###############################################################
#  Generated by:      Cadence Innovus 21.35-s114_1
#  OS:                Linux x86_64(Host ID pc231.ee.hacettepe.edu.tr)
#  Generated on:      Mon Dec 22 15:29:11 2025
#  Design:            mdu_macro
#  Command:           write_lef_abstract -5.8 mdu_macro.lef
###############################################################

VERSION 5.8 ;

BUSBITCHARS "[]" ;
DIVIDERCHAR "/" ;

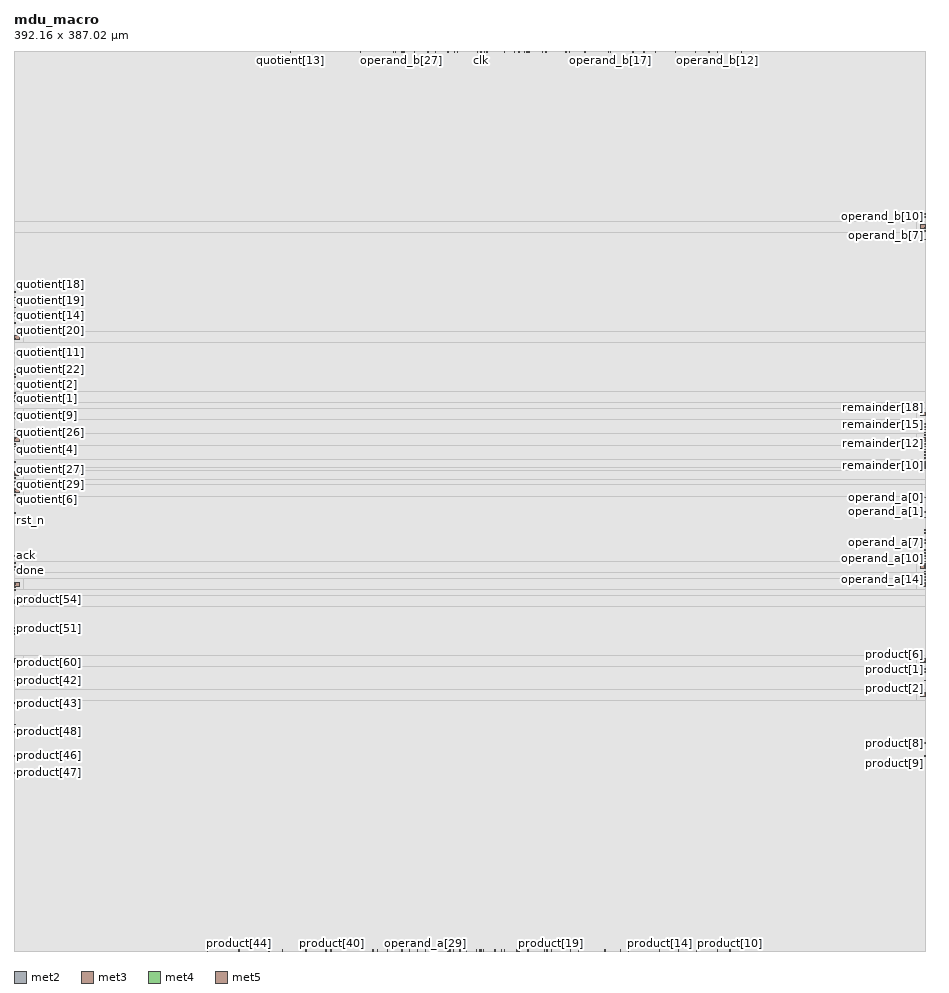
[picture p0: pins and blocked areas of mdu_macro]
MACRO mdu_macro
  CLASS BLOCK ;
  SIZE 392.160000 BY 387.020000 ;
  FOREIGN mdu_macro 0.000000 0.000000 ;
  ORIGIN 0 0 ;
  SYMMETRY X Y R90 ;
  PIN clk
    DIRECTION INPUT ;
    USE SIGNAL ;
    PORT
      LAYER met2 ;
        RECT 200.810000 386.535000 200.950000 387.020000 ;
    END
  END clk
  PIN rst_n
    DIRECTION INPUT ;
    USE SIGNAL ;
    PORT
      LAYER met3 ;
        RECT 0.000000 188.100000 0.800000 188.400000 ;
    END
  END rst_n
  PIN start
    DIRECTION INPUT ;
    USE SIGNAL ;
    PORT
      LAYER met3 ;
        RECT 0.000000 196.030000 0.800000 196.330000 ;
    END
  END start
  PIN ack
    DIRECTION INPUT ;
    USE SIGNAL ;
    PORT
      LAYER met3 ;
        RECT 0.000000 169.800000 0.800000 170.100000 ;
    END
  END ack
  PIN funct3[2]
    DIRECTION INPUT ;
    USE SIGNAL ;
    PORT
      LAYER met3 ;
        RECT 0.000000 198.470000 0.800000 198.770000 ;
    END
  END funct3[2]
  PIN funct3[1]
    DIRECTION INPUT ;
    USE SIGNAL ;
    PORT
      LAYER met2 ;
        RECT 186.410000 386.535000 186.550000 387.020000 ;
    END
  END funct3[1]
  PIN funct3[0]
    DIRECTION INPUT ;
    USE SIGNAL ;
    PORT
      LAYER met4 ;
        RECT 186.435000 386.220000 186.735000 387.020000 ;
    END
  END funct3[0]
  PIN operand_a[31]
    DIRECTION INPUT ;
    USE SIGNAL ;
    PORT
      LAYER met5 ;
        RECT 0.000000 197.210000 2.500000 198.810000 ;
    END
  END operand_a[31]
  PIN operand_a[30]
    DIRECTION INPUT ;
    USE SIGNAL ;
    PORT
      LAYER met2 ;
        RECT 170.090000 0.000000 170.230000 0.485000 ;
    END
  END operand_a[30]
  PIN operand_a[29]
    DIRECTION INPUT ;
    USE SIGNAL ;
    PORT
      LAYER met2 ;
        RECT 176.810000 0.000000 176.950000 0.485000 ;
    END
  END operand_a[29]
  PIN operand_a[28]
    DIRECTION INPUT ;
    USE SIGNAL ;
    PORT
      LAYER met2 ;
        RECT 186.410000 0.000000 186.550000 0.485000 ;
    END
  END operand_a[28]
  PIN operand_a[27]
    DIRECTION INPUT ;
    USE SIGNAL ;
    PORT
      LAYER met2 ;
        RECT 191.690000 0.000000 191.830000 0.485000 ;
    END
  END operand_a[27]
  PIN operand_a[26]
    DIRECTION INPUT ;
    USE SIGNAL ;
    PORT
      LAYER met2 ;
        RECT 198.890000 0.000000 199.030000 0.485000 ;
    END
  END operand_a[26]
  PIN operand_a[25]
    DIRECTION INPUT ;
    USE SIGNAL ;
    PORT
      LAYER met2 ;
        RECT 206.570000 0.000000 206.710000 0.485000 ;
    END
  END operand_a[25]
  PIN operand_a[24]
    DIRECTION INPUT ;
    USE SIGNAL ;
    PORT
      LAYER met2 ;
        RECT 210.890000 0.000000 211.030000 0.485000 ;
    END
  END operand_a[24]
  PIN operand_a[23]
    DIRECTION INPUT ;
    USE SIGNAL ;
    PORT
      LAYER met2 ;
        RECT 217.130000 0.000000 217.270000 0.485000 ;
    END
  END operand_a[23]
  PIN operand_a[22]
    DIRECTION INPUT ;
    USE SIGNAL ;
    PORT
      LAYER met2 ;
        RECT 220.970000 0.000000 221.110000 0.485000 ;
    END
  END operand_a[22]
  PIN operand_a[21]
    DIRECTION INPUT ;
    USE SIGNAL ;
    PORT
      LAYER met2 ;
        RECT 228.170000 0.000000 228.310000 0.485000 ;
    END
  END operand_a[21]
  PIN operand_a[20]
    DIRECTION INPUT ;
    USE SIGNAL ;
    PORT
      LAYER met3 ;
        RECT 391.360000 160.650000 392.160000 160.950000 ;
    END
  END operand_a[20]
  PIN operand_a[19]
    DIRECTION INPUT ;
    USE SIGNAL ;
    PORT
      LAYER met3 ;
        RECT 391.360000 158.210000 392.160000 158.510000 ;
    END
  END operand_a[19]
  PIN operand_a[18]
    DIRECTION INPUT ;
    USE SIGNAL ;
    PORT
      LAYER met3 ;
        RECT 391.360000 159.430000 392.160000 159.730000 ;
    END
  END operand_a[18]
  PIN operand_a[17]
    DIRECTION INPUT ;
    USE SIGNAL ;
    PORT
      LAYER met5 ;
        RECT 389.660000 156.950000 392.160000 158.550000 ;
    END
  END operand_a[17]
  PIN operand_a[16]
    DIRECTION INPUT ;
    USE SIGNAL ;
    PORT
      LAYER met3 ;
        RECT 391.360000 161.870000 392.160000 162.170000 ;
    END
  END operand_a[16]
  PIN operand_a[15]
    DIRECTION INPUT ;
    USE SIGNAL ;
    PORT
      LAYER met3 ;
        RECT 391.360000 164.920000 392.160000 165.220000 ;
    END
  END operand_a[15]
  PIN operand_a[14]
    DIRECTION INPUT ;
    USE SIGNAL ;
    PORT
      LAYER met3 ;
        RECT 391.360000 163.090000 392.160000 163.390000 ;
    END
  END operand_a[14]
  PIN operand_a[13]
    DIRECTION INPUT ;
    USE SIGNAL ;
    PORT
      LAYER met5 ;
        RECT 389.660000 164.270000 392.160000 165.870000 ;
    END
  END operand_a[13]
  PIN operand_a[12]
    DIRECTION INPUT ;
    USE SIGNAL ;
    PORT
      LAYER met3 ;
        RECT 391.360000 166.140000 392.160000 166.440000 ;
    END
  END operand_a[12]
  PIN operand_a[11]
    DIRECTION INPUT ;
    USE SIGNAL ;
    PORT
      LAYER met3 ;
        RECT 391.360000 167.360000 392.160000 167.660000 ;
    END
  END operand_a[11]
  PIN operand_a[10]
    DIRECTION INPUT ;
    USE SIGNAL ;
    PORT
      LAYER met3 ;
        RECT 391.360000 168.580000 392.160000 168.880000 ;
    END
  END operand_a[10]
  PIN operand_a[9]
    DIRECTION INPUT ;
    USE SIGNAL ;
    PORT
      LAYER met3 ;
        RECT 391.360000 169.800000 392.160000 170.100000 ;
    END
  END operand_a[9]
  PIN operand_a[8]
    DIRECTION INPUT ;
    USE SIGNAL ;
    PORT
      LAYER met3 ;
        RECT 391.360000 171.020000 392.160000 171.320000 ;
    END
  END operand_a[8]
  PIN operand_a[7]
    DIRECTION INPUT ;
    USE SIGNAL ;
    PORT
      LAYER met3 ;
        RECT 391.360000 172.240000 392.160000 172.540000 ;
    END
  END operand_a[7]
  PIN operand_a[6]
    DIRECTION INPUT ;
    USE SIGNAL ;
    PORT
      LAYER met3 ;
        RECT 391.360000 175.290000 392.160000 175.590000 ;
    END
  END operand_a[6]
  PIN operand_a[5]
    DIRECTION INPUT ;
    USE SIGNAL ;
    PORT
      LAYER met3 ;
        RECT 391.360000 176.510000 392.160000 176.810000 ;
    END
  END operand_a[5]
  PIN operand_a[4]
    DIRECTION INPUT ;
    USE SIGNAL ;
    PORT
      LAYER met3 ;
        RECT 391.360000 180.780000 392.160000 181.080000 ;
    END
  END operand_a[4]
  PIN operand_a[3]
    DIRECTION INPUT ;
    USE SIGNAL ;
    PORT
      LAYER met3 ;
        RECT 391.360000 179.560000 392.160000 179.860000 ;
    END
  END operand_a[3]
  PIN operand_a[2]
    DIRECTION INPUT ;
    USE SIGNAL ;
    PORT
      LAYER met3 ;
        RECT 391.360000 186.270000 392.160000 186.570000 ;
    END
  END operand_a[2]
  PIN operand_a[1]
    DIRECTION INPUT ;
    USE SIGNAL ;
    PORT
      LAYER met3 ;
        RECT 391.360000 188.710000 392.160000 189.010000 ;
    END
  END operand_a[1]
  PIN operand_a[0]
    DIRECTION INPUT ;
    USE SIGNAL ;
    PORT
      LAYER met3 ;
        RECT 391.360000 194.810000 392.160000 195.110000 ;
    END
  END operand_a[0]
  PIN operand_b[31]
    DIRECTION INPUT ;
    USE SIGNAL ;
    PORT
      LAYER met2 ;
        RECT 178.250000 386.535000 178.390000 387.020000 ;
    END
  END operand_b[31]
  PIN operand_b[30]
    DIRECTION INPUT ;
    USE SIGNAL ;
    PORT
      LAYER met2 ;
        RECT 172.010000 386.535000 172.150000 387.020000 ;
    END
  END operand_b[30]
  PIN operand_b[29]
    DIRECTION INPUT ;
    USE SIGNAL ;
    PORT
      LAYER met2 ;
        RECT 167.690000 386.535000 167.830000 387.020000 ;
    END
  END operand_b[29]
  PIN operand_b[28]
    DIRECTION INPUT ;
    USE SIGNAL ;
    PORT
      LAYER met2 ;
        RECT 163.850000 386.535000 163.990000 387.020000 ;
    END
  END operand_b[28]
  PIN operand_b[27]
    DIRECTION INPUT ;
    USE SIGNAL ;
    PORT
      LAYER met2 ;
        RECT 166.730000 386.535000 166.870000 387.020000 ;
    END
  END operand_b[27]
  PIN operand_b[26]
    DIRECTION INPUT ;
    USE SIGNAL ;
    PORT
      LAYER met2 ;
        RECT 181.130000 386.535000 181.270000 387.020000 ;
    END
  END operand_b[26]
  PIN operand_b[25]
    DIRECTION INPUT ;
    USE SIGNAL ;
    PORT
      LAYER met2 ;
        RECT 189.290000 386.535000 189.430000 387.020000 ;
    END
  END operand_b[25]
  PIN operand_b[24]
    DIRECTION INPUT ;
    USE SIGNAL ;
    PORT
      LAYER met2 ;
        RECT 202.250000 386.535000 202.390000 387.020000 ;
    END
  END operand_b[24]
  PIN operand_b[23]
    DIRECTION INPUT ;
    USE SIGNAL ;
    PORT
      LAYER met2 ;
        RECT 203.690000 386.535000 203.830000 387.020000 ;
    END
  END operand_b[23]
  PIN operand_b[22]
    DIRECTION INPUT ;
    USE SIGNAL ;
    PORT
      LAYER met2 ;
        RECT 210.890000 386.535000 211.030000 387.020000 ;
    END
  END operand_b[22]
  PIN operand_b[21]
    DIRECTION INPUT ;
    USE SIGNAL ;
    PORT
      LAYER met2 ;
        RECT 220.490000 386.535000 220.630000 387.020000 ;
    END
  END operand_b[21]
  PIN operand_b[20]
    DIRECTION INPUT ;
    USE SIGNAL ;
    PORT
      LAYER met2 ;
        RECT 227.210000 386.535000 227.350000 387.020000 ;
    END
  END operand_b[20]
  PIN operand_b[19]
    DIRECTION INPUT ;
    USE SIGNAL ;
    PORT
      LAYER met2 ;
        RECT 238.730000 386.535000 238.870000 387.020000 ;
    END
  END operand_b[19]
  PIN operand_b[18]
    DIRECTION INPUT ;
    USE SIGNAL ;
    PORT
      LAYER met2 ;
        RECT 245.450000 386.535000 245.590000 387.020000 ;
    END
  END operand_b[18]
  PIN operand_b[17]
    DIRECTION INPUT ;
    USE SIGNAL ;
    PORT
      LAYER met2 ;
        RECT 256.490000 386.535000 256.630000 387.020000 ;
    END
  END operand_b[17]
  PIN operand_b[16]
    DIRECTION INPUT ;
    USE SIGNAL ;
    PORT
      LAYER met2 ;
        RECT 266.090000 386.535000 266.230000 387.020000 ;
    END
  END operand_b[16]
  PIN operand_b[15]
    DIRECTION INPUT ;
    USE SIGNAL ;
    PORT
      LAYER met2 ;
        RECT 275.690000 386.535000 275.830000 387.020000 ;
    END
  END operand_b[15]
  PIN operand_b[14]
    DIRECTION INPUT ;
    USE SIGNAL ;
    PORT
      LAYER met2 ;
        RECT 284.330000 386.535000 284.470000 387.020000 ;
    END
  END operand_b[14]
  PIN operand_b[13]
    DIRECTION INPUT ;
    USE SIGNAL ;
    PORT
      LAYER met2 ;
        RECT 292.970000 386.535000 293.110000 387.020000 ;
    END
  END operand_b[13]
  PIN operand_b[12]
    DIRECTION INPUT ;
    USE SIGNAL ;
    PORT
      LAYER met2 ;
        RECT 302.570000 386.535000 302.710000 387.020000 ;
    END
  END operand_b[12]
  PIN operand_b[11]
    DIRECTION INPUT ;
    USE SIGNAL ;
    PORT
      LAYER met3 ;
        RECT 391.360000 316.810000 392.160000 317.110000 ;
    END
  END operand_b[11]
  PIN operand_b[10]
    DIRECTION INPUT ;
    USE SIGNAL ;
    PORT
      LAYER met3 ;
        RECT 391.360000 315.590000 392.160000 315.890000 ;
    END
  END operand_b[10]
  PIN operand_b[9]
    DIRECTION INPUT ;
    USE SIGNAL ;
    PORT
      LAYER met3 ;
        RECT 391.360000 309.490000 392.160000 309.790000 ;
    END
  END operand_b[9]
  PIN operand_b[8]
    DIRECTION INPUT ;
    USE SIGNAL ;
    PORT
      LAYER met3 ;
        RECT 391.360000 305.830000 392.160000 306.130000 ;
    END
  END operand_b[8]
  PIN operand_b[7]
    DIRECTION INPUT ;
    USE SIGNAL ;
    PORT
      LAYER met3 ;
        RECT 391.360000 310.710000 392.160000 311.010000 ;
    END
  END operand_b[7]
  PIN operand_b[6]
    DIRECTION INPUT ;
    USE SIGNAL ;
    PORT
      LAYER met5 ;
        RECT 389.660000 310.670000 392.160000 312.270000 ;
    END
  END operand_b[6]
  PIN operand_b[5]
    DIRECTION INPUT ;
    USE SIGNAL ;
    PORT
      LAYER met2 ;
        RECT 312.650000 386.535000 312.790000 387.020000 ;
    END
  END operand_b[5]
  PIN operand_b[4]
    DIRECTION INPUT ;
    USE SIGNAL ;
    PORT
      LAYER met2 ;
        RECT 298.730000 386.535000 298.870000 387.020000 ;
    END
  END operand_b[4]
  PIN operand_b[3]
    DIRECTION INPUT ;
    USE SIGNAL ;
    PORT
      LAYER met2 ;
        RECT 270.890000 386.535000 271.030000 387.020000 ;
    END
  END operand_b[3]
  PIN operand_b[2]
    DIRECTION INPUT ;
    USE SIGNAL ;
    PORT
      LAYER met2 ;
        RECT 255.530000 386.535000 255.670000 387.020000 ;
    END
  END operand_b[2]
  PIN operand_b[1]
    DIRECTION INPUT ;
    USE SIGNAL ;
    PORT
      LAYER met2 ;
        RECT 237.290000 386.535000 237.430000 387.020000 ;
    END
  END operand_b[1]
  PIN operand_b[0]
    DIRECTION INPUT ;
    USE SIGNAL ;
    PORT
      LAYER met2 ;
        RECT 219.530000 386.535000 219.670000 387.020000 ;
    END
  END operand_b[0]
  PIN busy
    DIRECTION OUTPUT ;
    USE SIGNAL ;
    PORT
      LAYER met5 ;
        RECT 0.000000 204.530000 2.500000 206.130000 ;
    END
  END busy
  PIN done
    DIRECTION OUTPUT ;
    USE SIGNAL ;
    PORT
      LAYER met3 ;
        RECT 0.000000 166.750000 0.800000 167.050000 ;
    END
  END done
  PIN product[63]
    DIRECTION OUTPUT ;
    USE SIGNAL ;
    PORT
      LAYER met3 ;
        RECT 0.000000 156.380000 0.800000 156.680000 ;
    END
  END product[63]
  PIN product[62]
    DIRECTION OUTPUT ;
    USE SIGNAL ;
    PORT
      LAYER met3 ;
        RECT 0.000000 137.470000 0.800000 137.770000 ;
    END
  END product[62]
  PIN product[61]
    DIRECTION OUTPUT ;
    USE SIGNAL ;
    PORT
      LAYER met2 ;
        RECT 125.450000 0.000000 125.590000 0.485000 ;
    END
  END product[61]
  PIN product[60]
    DIRECTION OUTPUT ;
    USE SIGNAL ;
    PORT
      LAYER met3 ;
        RECT 0.000000 124.050000 0.800000 124.350000 ;
    END
  END product[60]
  PIN product[59]
    DIRECTION OUTPUT ;
    USE SIGNAL ;
    PORT
      LAYER met3 ;
        RECT 0.000000 136.250000 0.800000 136.550000 ;
    END
  END product[59]
  PIN product[58]
    DIRECTION OUTPUT ;
    USE SIGNAL ;
    PORT
      LAYER met3 ;
        RECT 0.000000 155.160000 0.800000 155.460000 ;
    END
  END product[58]
  PIN product[57]
    DIRECTION OUTPUT ;
    USE SIGNAL ;
    PORT
      LAYER met3 ;
        RECT 0.000000 163.700000 0.800000 164.000000 ;
    END
  END product[57]
  PIN product[56]
    DIRECTION OUTPUT ;
    USE SIGNAL ;
    PORT
      LAYER met3 ;
        RECT 0.000000 164.920000 0.800000 165.220000 ;
    END
  END product[56]
  PIN product[55]
    DIRECTION OUTPUT ;
    USE SIGNAL ;
    PORT
      LAYER met3 ;
        RECT 0.000000 157.600000 0.800000 157.900000 ;
    END
  END product[55]
  PIN product[54]
    DIRECTION OUTPUT ;
    USE SIGNAL ;
    PORT
      LAYER met3 ;
        RECT 0.000000 150.890000 0.800000 151.190000 ;
    END
  END product[54]
  PIN product[53]
    DIRECTION OUTPUT ;
    USE SIGNAL ;
    PORT
      LAYER met5 ;
        RECT 0.000000 156.950000 2.500000 158.550000 ;
    END
  END product[53]
  PIN product[52]
    DIRECTION OUTPUT ;
    USE SIGNAL ;
    PORT
      LAYER met5 ;
        RECT 0.000000 149.630000 2.500000 151.230000 ;
    END
  END product[52]
  PIN product[51]
    DIRECTION OUTPUT ;
    USE SIGNAL ;
    PORT
      LAYER met3 ;
        RECT 0.000000 138.690000 0.800000 138.990000 ;
    END
  END product[51]
  PIN product[50]
    DIRECTION OUTPUT ;
    USE SIGNAL ;
    PORT
      LAYER met5 ;
        RECT 0.000000 124.010000 2.500000 125.610000 ;
    END
  END product[50]
  PIN product[49]
    DIRECTION OUTPUT ;
    USE SIGNAL ;
    PORT
      LAYER met3 ;
        RECT 0.000000 97.210000 0.800000 97.510000 ;
    END
  END product[49]
  PIN product[48]
    DIRECTION OUTPUT ;
    USE SIGNAL ;
    PORT
      LAYER met3 ;
        RECT 0.000000 94.160000 0.800000 94.460000 ;
    END
  END product[48]
  PIN product[47]
    DIRECTION OUTPUT ;
    USE SIGNAL ;
    PORT
      LAYER met3 ;
        RECT 0.000000 76.470000 0.800000 76.770000 ;
    END
  END product[47]
  PIN product[46]
    DIRECTION OUTPUT ;
    USE SIGNAL ;
    PORT
      LAYER met3 ;
        RECT 0.000000 83.790000 0.800000 84.090000 ;
    END
  END product[46]
  PIN product[45]
    DIRECTION OUTPUT ;
    USE SIGNAL ;
    PORT
      LAYER met2 ;
        RECT 83.210000 0.000000 83.350000 0.485000 ;
    END
  END product[45]
  PIN product[44]
    DIRECTION OUTPUT ;
    USE SIGNAL ;
    PORT
      LAYER met2 ;
        RECT 96.650000 0.000000 96.790000 0.485000 ;
    END
  END product[44]
  PIN product[43]
    DIRECTION OUTPUT ;
    USE SIGNAL ;
    PORT
      LAYER met3 ;
        RECT 0.000000 106.360000 0.800000 106.660000 ;
    END
  END product[43]
  PIN product[42]
    DIRECTION OUTPUT ;
    USE SIGNAL ;
    PORT
      LAYER met3 ;
        RECT 0.000000 116.120000 0.800000 116.420000 ;
    END
  END product[42]
  PIN product[41]
    DIRECTION OUTPUT ;
    USE SIGNAL ;
    PORT
      LAYER met2 ;
        RECT 134.090000 0.000000 134.230000 0.485000 ;
    END
  END product[41]
  PIN product[40]
    DIRECTION OUTPUT ;
    USE SIGNAL ;
    PORT
      LAYER met2 ;
        RECT 136.490000 0.000000 136.630000 0.485000 ;
    END
  END product[40]
  PIN product[39]
    DIRECTION OUTPUT ;
    USE SIGNAL ;
    PORT
      LAYER met2 ;
        RECT 109.610000 0.000000 109.750000 0.485000 ;
    END
  END product[39]
  PIN product[38]
    DIRECTION OUTPUT ;
    USE SIGNAL ;
    PORT
      LAYER met2 ;
        RECT 115.370000 0.000000 115.510000 0.485000 ;
    END
  END product[38]
  PIN product[37]
    DIRECTION OUTPUT ;
    USE SIGNAL ;
    PORT
      LAYER met4 ;
        RECT 136.005000 0.000000 136.305000 0.800000 ;
    END
  END product[37]
  PIN product[36]
    DIRECTION OUTPUT ;
    USE SIGNAL ;
    PORT
      LAYER met2 ;
        RECT 154.250000 0.000000 154.390000 0.485000 ;
    END
  END product[36]
  PIN product[35]
    DIRECTION OUTPUT ;
    USE SIGNAL ;
    PORT
      LAYER met2 ;
        RECT 166.730000 0.000000 166.870000 0.485000 ;
    END
  END product[35]
  PIN product[34]
    DIRECTION OUTPUT ;
    USE SIGNAL ;
    PORT
      LAYER met2 ;
        RECT 200.330000 0.000000 200.470000 0.485000 ;
    END
  END product[34]
  PIN product[33]
    DIRECTION OUTPUT ;
    USE SIGNAL ;
    PORT
      LAYER met2 ;
        RECT 194.570000 0.000000 194.710000 0.485000 ;
    END
  END product[33]
  PIN product[32]
    DIRECTION OUTPUT ;
    USE SIGNAL ;
    PORT
      LAYER met2 ;
        RECT 188.810000 0.000000 188.950000 0.485000 ;
    END
  END product[32]
  PIN product[31]
    DIRECTION OUTPUT ;
    USE SIGNAL ;
    PORT
      LAYER met2 ;
        RECT 187.370000 0.000000 187.510000 0.485000 ;
    END
  END product[31]
  PIN product[30]
    DIRECTION OUTPUT ;
    USE SIGNAL ;
    PORT
      LAYER met2 ;
        RECT 173.450000 0.000000 173.590000 0.485000 ;
    END
  END product[30]
  PIN product[29]
    DIRECTION OUTPUT ;
    USE SIGNAL ;
    PORT
      LAYER met2 ;
        RECT 160.490000 0.000000 160.630000 0.485000 ;
    END
  END product[29]
  PIN product[28]
    DIRECTION OUTPUT ;
    USE SIGNAL ;
    PORT
      LAYER met2 ;
        RECT 156.170000 0.000000 156.310000 0.485000 ;
    END
  END product[28]
  PIN product[27]
    DIRECTION OUTPUT ;
    USE SIGNAL ;
    PORT
      LAYER met4 ;
        RECT 186.435000 0.000000 186.735000 0.800000 ;
    END
  END product[27]
  PIN product[26]
    DIRECTION OUTPUT ;
    USE SIGNAL ;
    PORT
      LAYER met4 ;
        RECT 200.580000 0.000000 200.880000 0.800000 ;
    END
  END product[26]
  PIN product[25]
    DIRECTION OUTPUT ;
    USE SIGNAL ;
    PORT
      LAYER met2 ;
        RECT 201.770000 0.000000 201.910000 0.485000 ;
    END
  END product[25]
  PIN product[24]
    DIRECTION OUTPUT ;
    USE SIGNAL ;
    PORT
      LAYER met4 ;
        RECT 206.730000 0.000000 207.030000 0.800000 ;
    END
  END product[24]
  PIN product[23]
    DIRECTION OUTPUT ;
    USE SIGNAL ;
    PORT
      LAYER met2 ;
        RECT 209.450000 0.000000 209.590000 0.485000 ;
    END
  END product[23]
  PIN product[22]
    DIRECTION OUTPUT ;
    USE SIGNAL ;
    PORT
      LAYER met4 ;
        RECT 220.875000 0.000000 221.175000 0.800000 ;
    END
  END product[22]
  PIN product[21]
    DIRECTION OUTPUT ;
    USE SIGNAL ;
    PORT
      LAYER met2 ;
        RECT 229.130000 0.000000 229.270000 0.485000 ;
    END
  END product[21]
  PIN product[20]
    DIRECTION OUTPUT ;
    USE SIGNAL ;
    PORT
      LAYER met2 ;
        RECT 239.210000 0.000000 239.350000 0.485000 ;
    END
  END product[20]
  PIN product[19]
    DIRECTION OUTPUT ;
    USE SIGNAL ;
    PORT
      LAYER met2 ;
        RECT 231.050000 0.000000 231.190000 0.485000 ;
    END
  END product[19]
  PIN product[18]
    DIRECTION OUTPUT ;
    USE SIGNAL ;
    PORT
      LAYER met2 ;
        RECT 242.570000 0.000000 242.710000 0.485000 ;
    END
  END product[18]
  PIN product[17]
    DIRECTION OUTPUT ;
    USE SIGNAL ;
    PORT
      LAYER met2 ;
        RECT 254.090000 0.000000 254.230000 0.485000 ;
    END
  END product[17]
  PIN product[16]
    DIRECTION OUTPUT ;
    USE SIGNAL ;
    PORT
      LAYER met2 ;
        RECT 260.810000 0.000000 260.950000 0.485000 ;
    END
  END product[16]
  PIN product[15]
    DIRECTION OUTPUT ;
    USE SIGNAL ;
    PORT
      LAYER met2 ;
        RECT 264.170000 0.000000 264.310000 0.485000 ;
    END
  END product[15]
  PIN product[14]
    DIRECTION OUTPUT ;
    USE SIGNAL ;
    PORT
      LAYER met2 ;
        RECT 277.610000 0.000000 277.750000 0.485000 ;
    END
  END product[14]
  PIN product[13]
    DIRECTION OUTPUT ;
    USE SIGNAL ;
    PORT
      LAYER met2 ;
        RECT 285.770000 0.000000 285.910000 0.485000 ;
    END
  END product[13]
  PIN product[12]
    DIRECTION OUTPUT ;
    USE SIGNAL ;
    PORT
      LAYER met2 ;
        RECT 293.450000 0.000000 293.590000 0.485000 ;
    END
  END product[12]
  PIN product[11]
    DIRECTION OUTPUT ;
    USE SIGNAL ;
    PORT
      LAYER met2 ;
        RECT 302.570000 0.000000 302.710000 0.485000 ;
    END
  END product[11]
  PIN product[10]
    DIRECTION OUTPUT ;
    USE SIGNAL ;
    PORT
      LAYER met2 ;
        RECT 307.850000 0.000000 307.990000 0.485000 ;
    END
  END product[10]
  PIN product[9]
    DIRECTION OUTPUT ;
    USE SIGNAL ;
    PORT
      LAYER met3 ;
        RECT 391.360000 83.790000 392.160000 84.090000 ;
    END
  END product[9]
  PIN product[8]
    DIRECTION OUTPUT ;
    USE SIGNAL ;
    PORT
      LAYER met3 ;
        RECT 391.360000 89.280000 392.160000 89.580000 ;
    END
  END product[8]
  PIN product[7]
    DIRECTION OUTPUT ;
    USE SIGNAL ;
    PORT
      LAYER met3 ;
        RECT 391.360000 110.630000 392.160000 110.930000 ;
    END
  END product[7]
  PIN product[6]
    DIRECTION OUTPUT ;
    USE SIGNAL ;
    PORT
      LAYER met3 ;
        RECT 391.360000 124.050000 392.160000 124.350000 ;
    END
  END product[6]
  PIN product[5]
    DIRECTION OUTPUT ;
    USE SIGNAL ;
    PORT
      LAYER met5 ;
        RECT 389.660000 124.010000 392.160000 125.610000 ;
    END
  END product[5]
  PIN product[4]
    DIRECTION OUTPUT ;
    USE SIGNAL ;
    PORT
      LAYER met5 ;
        RECT 389.660000 109.370000 392.160000 110.970000 ;
    END
  END product[4]
  PIN product[3]
    DIRECTION OUTPUT ;
    USE SIGNAL ;
    PORT
      LAYER met3 ;
        RECT 391.360000 119.780000 392.160000 120.080000 ;
    END
  END product[3]
  PIN product[2]
    DIRECTION OUTPUT ;
    USE SIGNAL ;
    PORT
      LAYER met3 ;
        RECT 391.360000 116.120000 392.160000 116.420000 ;
    END
  END product[2]
  PIN product[1]
    DIRECTION OUTPUT ;
    USE SIGNAL ;
    PORT
      LAYER met3 ;
        RECT 391.360000 121.000000 392.160000 121.300000 ;
    END
  END product[1]
  PIN product[0]
    DIRECTION OUTPUT ;
    USE SIGNAL ;
    PORT
      LAYER met2 ;
        RECT 216.170000 0.000000 216.310000 0.485000 ;
    END
  END product[0]
  PIN quotient[31]
    DIRECTION OUTPUT ;
    USE SIGNAL ;
    PORT
      LAYER met3 ;
        RECT 0.000000 220.430000 0.800000 220.730000 ;
    END
  END quotient[31]
  PIN quotient[30]
    DIRECTION OUTPUT ;
    USE SIGNAL ;
    PORT
      LAYER met5 ;
        RECT 0.000000 219.170000 2.500000 220.770000 ;
    END
  END quotient[30]
  PIN quotient[29]
    DIRECTION OUTPUT ;
    USE SIGNAL ;
    PORT
      LAYER met3 ;
        RECT 0.000000 200.300000 0.800000 200.600000 ;
    END
  END quotient[29]
  PIN quotient[28]
    DIRECTION OUTPUT ;
    USE SIGNAL ;
    PORT
      LAYER met3 ;
        RECT 0.000000 203.350000 0.800000 203.650000 ;
    END
  END quotient[28]
  PIN quotient[27]
    DIRECTION OUTPUT ;
    USE SIGNAL ;
    PORT
      LAYER met3 ;
        RECT 0.000000 210.060000 0.800000 210.360000 ;
    END
  END quotient[27]
  PIN quotient[26]
    DIRECTION OUTPUT ;
    USE SIGNAL ;
    PORT
      LAYER met3 ;
        RECT 0.000000 222.870000 0.800000 223.170000 ;
    END
  END quotient[26]
  PIN quotient[25]
    DIRECTION OUTPUT ;
    USE SIGNAL ;
    PORT
      LAYER met3 ;
        RECT 0.000000 236.290000 0.800000 236.590000 ;
    END
  END quotient[25]
  PIN quotient[24]
    DIRECTION OUTPUT ;
    USE SIGNAL ;
    PORT
      LAYER met3 ;
        RECT 0.000000 246.660000 0.800000 246.960000 ;
    END
  END quotient[24]
  PIN quotient[23]
    DIRECTION OUTPUT ;
    USE SIGNAL ;
    PORT
      LAYER met3 ;
        RECT 0.000000 239.950000 0.800000 240.250000 ;
    END
  END quotient[23]
  PIN quotient[22]
    DIRECTION OUTPUT ;
    USE SIGNAL ;
    PORT
      LAYER met3 ;
        RECT 0.000000 249.710000 0.800000 250.010000 ;
    END
  END quotient[22]
  PIN quotient[21]
    DIRECTION OUTPUT ;
    USE SIGNAL ;
    PORT
      LAYER met3 ;
        RECT 0.000000 263.130000 0.800000 263.430000 ;
    END
  END quotient[21]
  PIN quotient[20]
    DIRECTION OUTPUT ;
    USE SIGNAL ;
    PORT
      LAYER met3 ;
        RECT 0.000000 269.840000 0.800000 270.140000 ;
    END
  END quotient[20]
  PIN quotient[19]
    DIRECTION OUTPUT ;
    USE SIGNAL ;
    PORT
      LAYER met3 ;
        RECT 0.000000 279.600000 0.800000 279.900000 ;
    END
  END quotient[19]
  PIN quotient[18]
    DIRECTION OUTPUT ;
    USE SIGNAL ;
    PORT
      LAYER met3 ;
        RECT 0.000000 283.260000 0.800000 283.560000 ;
    END
  END quotient[18]
  PIN quotient[17]
    DIRECTION OUTPUT ;
    USE SIGNAL ;
    PORT
      LAYER met3 ;
        RECT 0.000000 280.820000 0.800000 281.120000 ;
    END
  END quotient[17]
  PIN quotient[16]
    DIRECTION OUTPUT ;
    USE SIGNAL ;
    PORT
      LAYER met3 ;
        RECT 0.000000 272.890000 0.800000 273.190000 ;
    END
  END quotient[16]
  PIN quotient[15]
    DIRECTION OUTPUT ;
    USE SIGNAL ;
    PORT
      LAYER met3 ;
        RECT 0.000000 274.110000 0.800000 274.410000 ;
    END
  END quotient[15]
  PIN quotient[14]
    DIRECTION OUTPUT ;
    USE SIGNAL ;
    PORT
      LAYER met3 ;
        RECT 0.000000 276.550000 0.800000 276.850000 ;
    END
  END quotient[14]
  PIN quotient[13]
    DIRECTION OUTPUT ;
    USE SIGNAL ;
    PORT
      LAYER met2 ;
        RECT 118.730000 386.535000 118.870000 387.020000 ;
    END
  END quotient[13]
  PIN quotient[12]
    DIRECTION OUTPUT ;
    USE SIGNAL ;
    PORT
      LAYER met5 ;
        RECT 0.000000 263.090000 2.500000 264.690000 ;
    END
  END quotient[12]
  PIN quotient[11]
    DIRECTION OUTPUT ;
    USE SIGNAL ;
    PORT
      LAYER met3 ;
        RECT 0.000000 257.030000 0.800000 257.330000 ;
    END
  END quotient[11]
  PIN quotient[10]
    DIRECTION OUTPUT ;
    USE SIGNAL ;
    PORT
      LAYER met3 ;
        RECT 0.000000 247.880000 0.800000 248.180000 ;
    END
  END quotient[10]
  PIN quotient[9]
    DIRECTION OUTPUT ;
    USE SIGNAL ;
    PORT
      LAYER met3 ;
        RECT 0.000000 230.190000 0.800000 230.490000 ;
    END
  END quotient[9]
  PIN quotient[8]
    DIRECTION OUTPUT ;
    USE SIGNAL ;
    PORT
      LAYER met3 ;
        RECT 0.000000 216.770000 0.800000 217.070000 ;
    END
  END quotient[8]
  PIN quotient[7]
    DIRECTION OUTPUT ;
    USE SIGNAL ;
    PORT
      LAYER met3 ;
        RECT 0.000000 201.520000 0.800000 201.820000 ;
    END
  END quotient[7]
  PIN quotient[6]
    DIRECTION OUTPUT ;
    USE SIGNAL ;
    PORT
      LAYER met3 ;
        RECT 0.000000 197.250000 0.800000 197.550000 ;
    END
  END quotient[6]
  PIN quotient[5]
    DIRECTION OUTPUT ;
    USE SIGNAL ;
    PORT
      LAYER met3 ;
        RECT 0.000000 204.570000 0.800000 204.870000 ;
    END
  END quotient[5]
  PIN quotient[4]
    DIRECTION OUTPUT ;
    USE SIGNAL ;
    PORT
      LAYER met3 ;
        RECT 0.000000 215.550000 0.800000 215.850000 ;
    END
  END quotient[4]
  PIN quotient[3]
    DIRECTION OUTPUT ;
    USE SIGNAL ;
    PORT
      LAYER met5 ;
        RECT 0.000000 230.150000 2.500000 231.750000 ;
    END
  END quotient[3]
  PIN quotient[2]
    DIRECTION OUTPUT ;
    USE SIGNAL ;
    PORT
      LAYER met3 ;
        RECT 0.000000 243.610000 0.800000 243.910000 ;
    END
  END quotient[2]
  PIN quotient[1]
    DIRECTION OUTPUT ;
    USE SIGNAL ;
    PORT
      LAYER met3 ;
        RECT 0.000000 237.510000 0.800000 237.810000 ;
    END
  END quotient[1]
  PIN quotient[0]
    DIRECTION OUTPUT ;
    USE SIGNAL ;
    PORT
      LAYER met5 ;
        RECT 0.000000 237.470000 2.500000 239.070000 ;
    END
  END quotient[0]
  PIN remainder[31]
    DIRECTION OUTPUT ;
    USE SIGNAL ;
    PORT
      LAYER met2 ;
        RECT 148.970000 386.535000 149.110000 387.020000 ;
    END
  END remainder[31]
  PIN remainder[30]
    DIRECTION OUTPUT ;
    USE SIGNAL ;
    PORT
      LAYER met3 ;
        RECT 0.000000 217.990000 0.800000 218.290000 ;
    END
  END remainder[30]
  PIN remainder[29]
    DIRECTION OUTPUT ;
    USE SIGNAL ;
    PORT
      LAYER met3 ;
        RECT 0.000000 224.090000 0.800000 224.390000 ;
    END
  END remainder[29]
  PIN remainder[28]
    DIRECTION OUTPUT ;
    USE SIGNAL ;
    PORT
      LAYER met3 ;
        RECT 0.000000 228.970000 0.800000 229.270000 ;
    END
  END remainder[28]
  PIN remainder[27]
    DIRECTION OUTPUT ;
    USE SIGNAL ;
    PORT
      LAYER met4 ;
        RECT 163.065000 386.220000 163.365000 387.020000 ;
    END
  END remainder[27]
  PIN remainder[26]
    DIRECTION OUTPUT ;
    USE SIGNAL ;
    PORT
      LAYER met4 ;
        RECT 177.825000 386.220000 178.125000 387.020000 ;
    END
  END remainder[26]
  PIN remainder[25]
    DIRECTION OUTPUT ;
    USE SIGNAL ;
    PORT
      LAYER met2 ;
        RECT 190.730000 386.535000 190.870000 387.020000 ;
    END
  END remainder[25]
  PIN remainder[24]
    DIRECTION OUTPUT ;
    USE SIGNAL ;
    PORT
      LAYER met2 ;
        RECT 199.370000 386.535000 199.510000 387.020000 ;
    END
  END remainder[24]
  PIN remainder[23]
    DIRECTION OUTPUT ;
    USE SIGNAL ;
    PORT
      LAYER met2 ;
        RECT 215.210000 386.535000 215.350000 387.020000 ;
    END
  END remainder[23]
  PIN remainder[22]
    DIRECTION OUTPUT ;
    USE SIGNAL ;
    PORT
      LAYER met4 ;
        RECT 203.040000 386.220000 203.340000 387.020000 ;
    END
  END remainder[22]
  PIN remainder[21]
    DIRECTION OUTPUT ;
    USE SIGNAL ;
    PORT
      LAYER met2 ;
        RECT 217.130000 386.535000 217.270000 387.020000 ;
    END
  END remainder[21]
  PIN remainder[20]
    DIRECTION OUTPUT ;
    USE SIGNAL ;
    PORT
      LAYER met2 ;
        RECT 221.450000 386.535000 221.590000 387.020000 ;
    END
  END remainder[20]
  PIN remainder[19]
    DIRECTION OUTPUT ;
    USE SIGNAL ;
    PORT
      LAYER met2 ;
        RECT 228.650000 386.535000 228.790000 387.020000 ;
    END
  END remainder[19]
  PIN remainder[18]
    DIRECTION OUTPUT ;
    USE SIGNAL ;
    PORT
      LAYER met3 ;
        RECT 391.360000 230.190000 392.160000 230.490000 ;
    END
  END remainder[18]
  PIN remainder[17]
    DIRECTION OUTPUT ;
    USE SIGNAL ;
    PORT
      LAYER met3 ;
        RECT 391.360000 219.820000 392.160000 220.120000 ;
    END
  END remainder[17]
  PIN remainder[16]
    DIRECTION OUTPUT ;
    USE SIGNAL ;
    PORT
      LAYER met5 ;
        RECT 389.660000 219.170000 392.160000 220.770000 ;
    END
  END remainder[16]
  PIN remainder[15]
    DIRECTION OUTPUT ;
    USE SIGNAL ;
    PORT
      LAYER met3 ;
        RECT 391.360000 222.870000 392.160000 223.170000 ;
    END
  END remainder[15]
  PIN remainder[14]
    DIRECTION OUTPUT ;
    USE SIGNAL ;
    PORT
      LAYER met3 ;
        RECT 391.360000 216.770000 392.160000 217.070000 ;
    END
  END remainder[14]
  PIN remainder[13]
    DIRECTION OUTPUT ;
    USE SIGNAL ;
    PORT
      LAYER met3 ;
        RECT 391.360000 215.550000 392.160000 215.850000 ;
    END
  END remainder[13]
  PIN remainder[12]
    DIRECTION OUTPUT ;
    USE SIGNAL ;
    PORT
      LAYER met3 ;
        RECT 391.360000 217.990000 392.160000 218.290000 ;
    END
  END remainder[12]
  PIN remainder[11]
    DIRECTION OUTPUT ;
    USE SIGNAL ;
    PORT
      LAYER met3 ;
        RECT 391.360000 210.060000 392.160000 210.360000 ;
    END
  END remainder[11]
  PIN remainder[10]
    DIRECTION OUTPUT ;
    USE SIGNAL ;
    PORT
      LAYER met3 ;
        RECT 391.360000 208.840000 392.160000 209.140000 ;
    END
  END remainder[10]
  PIN remainder[9]
    DIRECTION OUTPUT ;
    USE SIGNAL ;
    PORT
      LAYER met5 ;
        RECT 389.660000 230.150000 392.160000 231.750000 ;
    END
  END remainder[9]
  PIN remainder[8]
    DIRECTION OUTPUT ;
    USE SIGNAL ;
    PORT
      LAYER met3 ;
        RECT 391.360000 224.090000 392.160000 224.390000 ;
    END
  END remainder[8]
  PIN remainder[7]
    DIRECTION OUTPUT ;
    USE SIGNAL ;
    PORT
      LAYER met3 ;
        RECT 391.360000 214.330000 392.160000 214.630000 ;
    END
  END remainder[7]
  PIN remainder[6]
    DIRECTION OUTPUT ;
    USE SIGNAL ;
    PORT
      LAYER met3 ;
        RECT 391.360000 213.110000 392.160000 213.410000 ;
    END
  END remainder[6]
  PIN remainder[5]
    DIRECTION OUTPUT ;
    USE SIGNAL ;
    PORT
      LAYER met3 ;
        RECT 391.360000 221.650000 392.160000 221.950000 ;
    END
  END remainder[5]
  PIN remainder[4]
    DIRECTION OUTPUT ;
    USE SIGNAL ;
    PORT
      LAYER met5 ;
        RECT 389.660000 208.190000 392.160000 209.790000 ;
    END
  END remainder[4]
  PIN remainder[3]
    DIRECTION OUTPUT ;
    USE SIGNAL ;
    PORT
      LAYER met3 ;
        RECT 391.360000 211.890000 392.160000 212.190000 ;
    END
  END remainder[3]
  PIN remainder[2]
    DIRECTION OUTPUT ;
    USE SIGNAL ;
    PORT
      LAYER met3 ;
        RECT 391.360000 207.620000 392.160000 207.920000 ;
    END
  END remainder[2]
  PIN remainder[1]
    DIRECTION OUTPUT ;
    USE SIGNAL ;
    PORT
      LAYER met3 ;
        RECT 391.360000 225.310000 392.160000 225.610000 ;
    END
  END remainder[1]
  PIN remainder[0]
    DIRECTION OUTPUT ;
    USE SIGNAL ;
    PORT
      LAYER met3 ;
        RECT 391.360000 226.530000 392.160000 226.830000 ;
    END
  END remainder[0]
  OBS
    LAYER met1 ;
      RECT 0.000000 0.000000 392.160000 387.020000 ;
    LAYER met2 ;
      RECT 312.930000 386.395000 392.160000 387.020000 ;
      RECT 302.850000 386.395000 312.510000 387.020000 ;
      RECT 299.010000 386.395000 302.430000 387.020000 ;
      RECT 293.250000 386.395000 298.590000 387.020000 ;
      RECT 284.610000 386.395000 292.830000 387.020000 ;
      RECT 275.970000 386.395000 284.190000 387.020000 ;
      RECT 271.170000 386.395000 275.550000 387.020000 ;
      RECT 266.370000 386.395000 270.750000 387.020000 ;
      RECT 256.770000 386.395000 265.950000 387.020000 ;
      RECT 255.810000 386.395000 256.350000 387.020000 ;
      RECT 245.730000 386.395000 255.390000 387.020000 ;
      RECT 239.010000 386.395000 245.310000 387.020000 ;
      RECT 237.570000 386.395000 238.590000 387.020000 ;
      RECT 228.930000 386.395000 237.150000 387.020000 ;
      RECT 227.490000 386.395000 228.510000 387.020000 ;
      RECT 221.730000 386.395000 227.070000 387.020000 ;
      RECT 220.770000 386.395000 221.310000 387.020000 ;
      RECT 219.810000 386.395000 220.350000 387.020000 ;
      RECT 217.410000 386.395000 219.390000 387.020000 ;
      RECT 215.490000 386.395000 216.990000 387.020000 ;
      RECT 211.170000 386.395000 215.070000 387.020000 ;
      RECT 203.970000 386.395000 210.750000 387.020000 ;
      RECT 202.530000 386.395000 203.550000 387.020000 ;
      RECT 201.090000 386.395000 202.110000 387.020000 ;
      RECT 199.650000 386.395000 200.670000 387.020000 ;
      RECT 191.010000 386.395000 199.230000 387.020000 ;
      RECT 189.570000 386.395000 190.590000 387.020000 ;
      RECT 186.690000 386.395000 189.150000 387.020000 ;
      RECT 181.410000 386.395000 186.270000 387.020000 ;
      RECT 178.530000 386.395000 180.990000 387.020000 ;
      RECT 172.290000 386.395000 178.110000 387.020000 ;
      RECT 167.970000 386.395000 171.870000 387.020000 ;
      RECT 167.010000 386.395000 167.550000 387.020000 ;
      RECT 164.130000 386.395000 166.590000 387.020000 ;
      RECT 149.250000 386.395000 163.710000 387.020000 ;
      RECT 119.010000 386.395000 148.830000 387.020000 ;
      RECT 0.000000 386.395000 118.590000 387.020000 ;
      RECT 0.000000 0.625000 392.160000 386.395000 ;
      RECT 308.130000 0.000000 392.160000 0.625000 ;
      RECT 302.850000 0.000000 307.710000 0.625000 ;
      RECT 293.730000 0.000000 302.430000 0.625000 ;
      RECT 286.050000 0.000000 293.310000 0.625000 ;
      RECT 277.890000 0.000000 285.630000 0.625000 ;
      RECT 264.450000 0.000000 277.470000 0.625000 ;
      RECT 261.090000 0.000000 264.030000 0.625000 ;
      RECT 254.370000 0.000000 260.670000 0.625000 ;
      RECT 242.850000 0.000000 253.950000 0.625000 ;
      RECT 239.490000 0.000000 242.430000 0.625000 ;
      RECT 231.330000 0.000000 239.070000 0.625000 ;
      RECT 229.410000 0.000000 230.910000 0.625000 ;
      RECT 228.450000 0.000000 228.990000 0.625000 ;
      RECT 221.250000 0.000000 228.030000 0.625000 ;
      RECT 217.410000 0.000000 220.830000 0.625000 ;
      RECT 216.450000 0.000000 216.990000 0.625000 ;
      RECT 211.170000 0.000000 216.030000 0.625000 ;
      RECT 209.730000 0.000000 210.750000 0.625000 ;
      RECT 206.850000 0.000000 209.310000 0.625000 ;
      RECT 202.050000 0.000000 206.430000 0.625000 ;
      RECT 200.610000 0.000000 201.630000 0.625000 ;
      RECT 199.170000 0.000000 200.190000 0.625000 ;
      RECT 194.850000 0.000000 198.750000 0.625000 ;
      RECT 191.970000 0.000000 194.430000 0.625000 ;
      RECT 189.090000 0.000000 191.550000 0.625000 ;
      RECT 187.650000 0.000000 188.670000 0.625000 ;
      RECT 186.690000 0.000000 187.230000 0.625000 ;
      RECT 177.090000 0.000000 186.270000 0.625000 ;
      RECT 173.730000 0.000000 176.670000 0.625000 ;
      RECT 170.370000 0.000000 173.310000 0.625000 ;
      RECT 167.010000 0.000000 169.950000 0.625000 ;
      RECT 160.770000 0.000000 166.590000 0.625000 ;
      RECT 156.450000 0.000000 160.350000 0.625000 ;
      RECT 154.530000 0.000000 156.030000 0.625000 ;
      RECT 136.770000 0.000000 154.110000 0.625000 ;
      RECT 134.370000 0.000000 136.350000 0.625000 ;
      RECT 125.730000 0.000000 133.950000 0.625000 ;
      RECT 115.650000 0.000000 125.310000 0.625000 ;
      RECT 109.890000 0.000000 115.230000 0.625000 ;
      RECT 96.930000 0.000000 109.470000 0.625000 ;
      RECT 83.490000 0.000000 96.510000 0.625000 ;
      RECT 0.000000 0.000000 83.070000 0.625000 ;
    LAYER met3 ;
      RECT 0.000000 317.410000 392.160000 387.020000 ;
      RECT 0.000000 316.510000 391.060000 317.410000 ;
      RECT 0.000000 316.190000 392.160000 316.510000 ;
      RECT 0.000000 315.290000 391.060000 316.190000 ;
      RECT 0.000000 311.310000 392.160000 315.290000 ;
      RECT 0.000000 310.410000 391.060000 311.310000 ;
      RECT 0.000000 310.090000 392.160000 310.410000 ;
      RECT 0.000000 309.190000 391.060000 310.090000 ;
      RECT 0.000000 306.430000 392.160000 309.190000 ;
      RECT 0.000000 305.530000 391.060000 306.430000 ;
      RECT 0.000000 283.860000 392.160000 305.530000 ;
      RECT 1.100000 282.960000 392.160000 283.860000 ;
      RECT 0.000000 281.420000 392.160000 282.960000 ;
      RECT 1.100000 280.520000 392.160000 281.420000 ;
      RECT 0.000000 280.200000 392.160000 280.520000 ;
      RECT 1.100000 279.300000 392.160000 280.200000 ;
      RECT 0.000000 277.150000 392.160000 279.300000 ;
      RECT 1.100000 276.250000 392.160000 277.150000 ;
      RECT 0.000000 274.710000 392.160000 276.250000 ;
      RECT 1.100000 273.810000 392.160000 274.710000 ;
      RECT 0.000000 273.490000 392.160000 273.810000 ;
      RECT 1.100000 272.590000 392.160000 273.490000 ;
      RECT 0.000000 270.440000 392.160000 272.590000 ;
      RECT 1.100000 269.540000 392.160000 270.440000 ;
      RECT 0.000000 263.730000 392.160000 269.540000 ;
      RECT 1.100000 262.830000 392.160000 263.730000 ;
      RECT 0.000000 257.630000 392.160000 262.830000 ;
      RECT 1.100000 256.730000 392.160000 257.630000 ;
      RECT 0.000000 250.310000 392.160000 256.730000 ;
      RECT 1.100000 249.410000 392.160000 250.310000 ;
      RECT 0.000000 248.480000 392.160000 249.410000 ;
      RECT 1.100000 247.580000 392.160000 248.480000 ;
      RECT 0.000000 247.260000 392.160000 247.580000 ;
      RECT 1.100000 246.360000 392.160000 247.260000 ;
      RECT 0.000000 244.210000 392.160000 246.360000 ;
      RECT 1.100000 243.310000 392.160000 244.210000 ;
      RECT 0.000000 240.550000 392.160000 243.310000 ;
      RECT 1.100000 239.650000 392.160000 240.550000 ;
      RECT 0.000000 238.110000 392.160000 239.650000 ;
      RECT 1.100000 237.210000 392.160000 238.110000 ;
      RECT 0.000000 236.890000 392.160000 237.210000 ;
      RECT 1.100000 235.990000 392.160000 236.890000 ;
      RECT 0.000000 230.790000 392.160000 235.990000 ;
      RECT 1.100000 229.890000 391.060000 230.790000 ;
      RECT 0.000000 229.570000 392.160000 229.890000 ;
      RECT 1.100000 228.670000 392.160000 229.570000 ;
      RECT 0.000000 227.130000 392.160000 228.670000 ;
      RECT 0.000000 226.230000 391.060000 227.130000 ;
      RECT 0.000000 225.910000 392.160000 226.230000 ;
      RECT 0.000000 225.010000 391.060000 225.910000 ;
      RECT 0.000000 224.690000 392.160000 225.010000 ;
      RECT 1.100000 223.790000 391.060000 224.690000 ;
      RECT 0.000000 223.470000 392.160000 223.790000 ;
      RECT 1.100000 222.570000 391.060000 223.470000 ;
      RECT 0.000000 222.250000 392.160000 222.570000 ;
      RECT 0.000000 221.350000 391.060000 222.250000 ;
      RECT 0.000000 221.030000 392.160000 221.350000 ;
      RECT 1.100000 220.420000 392.160000 221.030000 ;
      RECT 1.100000 220.130000 391.060000 220.420000 ;
      RECT 0.000000 219.520000 391.060000 220.130000 ;
      RECT 0.000000 218.590000 392.160000 219.520000 ;
      RECT 1.100000 217.690000 391.060000 218.590000 ;
      RECT 0.000000 217.370000 392.160000 217.690000 ;
      RECT 1.100000 216.470000 391.060000 217.370000 ;
      RECT 0.000000 216.150000 392.160000 216.470000 ;
      RECT 1.100000 215.250000 391.060000 216.150000 ;
      RECT 0.000000 214.930000 392.160000 215.250000 ;
      RECT 0.000000 214.030000 391.060000 214.930000 ;
      RECT 0.000000 213.710000 392.160000 214.030000 ;
      RECT 0.000000 212.810000 391.060000 213.710000 ;
      RECT 0.000000 212.490000 392.160000 212.810000 ;
      RECT 0.000000 211.590000 391.060000 212.490000 ;
      RECT 0.000000 210.660000 392.160000 211.590000 ;
      RECT 1.100000 209.760000 391.060000 210.660000 ;
      RECT 0.000000 209.440000 392.160000 209.760000 ;
      RECT 0.000000 208.540000 391.060000 209.440000 ;
      RECT 0.000000 208.220000 392.160000 208.540000 ;
      RECT 0.000000 207.320000 391.060000 208.220000 ;
      RECT 0.000000 205.170000 392.160000 207.320000 ;
      RECT 1.100000 204.270000 392.160000 205.170000 ;
      RECT 0.000000 203.950000 392.160000 204.270000 ;
      RECT 1.100000 203.050000 392.160000 203.950000 ;
      RECT 0.000000 202.120000 392.160000 203.050000 ;
      RECT 1.100000 201.220000 392.160000 202.120000 ;
      RECT 0.000000 200.900000 392.160000 201.220000 ;
      RECT 1.100000 200.000000 392.160000 200.900000 ;
      RECT 0.000000 199.070000 392.160000 200.000000 ;
      RECT 1.100000 198.170000 392.160000 199.070000 ;
      RECT 0.000000 197.850000 392.160000 198.170000 ;
      RECT 1.100000 196.950000 392.160000 197.850000 ;
      RECT 0.000000 196.630000 392.160000 196.950000 ;
      RECT 1.100000 195.730000 392.160000 196.630000 ;
      RECT 0.000000 195.410000 392.160000 195.730000 ;
      RECT 0.000000 194.510000 391.060000 195.410000 ;
      RECT 0.000000 189.310000 392.160000 194.510000 ;
      RECT 0.000000 188.700000 391.060000 189.310000 ;
      RECT 1.100000 188.410000 391.060000 188.700000 ;
      RECT 1.100000 187.800000 392.160000 188.410000 ;
      RECT 0.000000 186.870000 392.160000 187.800000 ;
      RECT 0.000000 185.970000 391.060000 186.870000 ;
      RECT 0.000000 181.380000 392.160000 185.970000 ;
      RECT 0.000000 180.480000 391.060000 181.380000 ;
      RECT 0.000000 180.160000 392.160000 180.480000 ;
      RECT 0.000000 179.260000 391.060000 180.160000 ;
      RECT 0.000000 177.110000 392.160000 179.260000 ;
      RECT 0.000000 176.210000 391.060000 177.110000 ;
      RECT 0.000000 175.890000 392.160000 176.210000 ;
      RECT 0.000000 174.990000 391.060000 175.890000 ;
      RECT 0.000000 172.840000 392.160000 174.990000 ;
      RECT 0.000000 171.940000 391.060000 172.840000 ;
      RECT 0.000000 171.620000 392.160000 171.940000 ;
      RECT 0.000000 170.720000 391.060000 171.620000 ;
      RECT 0.000000 170.400000 392.160000 170.720000 ;
      RECT 1.100000 169.500000 391.060000 170.400000 ;
      RECT 0.000000 169.180000 392.160000 169.500000 ;
      RECT 0.000000 168.280000 391.060000 169.180000 ;
      RECT 0.000000 167.960000 392.160000 168.280000 ;
      RECT 0.000000 167.350000 391.060000 167.960000 ;
      RECT 1.100000 167.060000 391.060000 167.350000 ;
      RECT 1.100000 166.740000 392.160000 167.060000 ;
      RECT 1.100000 166.450000 391.060000 166.740000 ;
      RECT 0.000000 165.840000 391.060000 166.450000 ;
      RECT 0.000000 165.520000 392.160000 165.840000 ;
      RECT 1.100000 164.620000 391.060000 165.520000 ;
      RECT 0.000000 164.300000 392.160000 164.620000 ;
      RECT 1.100000 163.690000 392.160000 164.300000 ;
      RECT 1.100000 163.400000 391.060000 163.690000 ;
      RECT 0.000000 162.790000 391.060000 163.400000 ;
      RECT 0.000000 162.470000 392.160000 162.790000 ;
      RECT 0.000000 161.570000 391.060000 162.470000 ;
      RECT 0.000000 161.250000 392.160000 161.570000 ;
      RECT 0.000000 160.350000 391.060000 161.250000 ;
      RECT 0.000000 160.030000 392.160000 160.350000 ;
      RECT 0.000000 159.130000 391.060000 160.030000 ;
      RECT 0.000000 158.810000 392.160000 159.130000 ;
      RECT 0.000000 158.200000 391.060000 158.810000 ;
      RECT 1.100000 157.910000 391.060000 158.200000 ;
      RECT 1.100000 157.300000 392.160000 157.910000 ;
      RECT 0.000000 156.980000 392.160000 157.300000 ;
      RECT 1.100000 156.080000 392.160000 156.980000 ;
      RECT 0.000000 155.760000 392.160000 156.080000 ;
      RECT 1.100000 154.860000 392.160000 155.760000 ;
      RECT 0.000000 151.490000 392.160000 154.860000 ;
      RECT 1.100000 150.590000 392.160000 151.490000 ;
      RECT 0.000000 139.290000 392.160000 150.590000 ;
      RECT 1.100000 138.390000 392.160000 139.290000 ;
      RECT 0.000000 138.070000 392.160000 138.390000 ;
      RECT 1.100000 137.170000 392.160000 138.070000 ;
      RECT 0.000000 136.850000 392.160000 137.170000 ;
      RECT 1.100000 135.950000 392.160000 136.850000 ;
      RECT 0.000000 124.650000 392.160000 135.950000 ;
      RECT 1.100000 123.750000 391.060000 124.650000 ;
      RECT 0.000000 121.600000 392.160000 123.750000 ;
      RECT 0.000000 120.700000 391.060000 121.600000 ;
      RECT 0.000000 120.380000 392.160000 120.700000 ;
      RECT 0.000000 119.480000 391.060000 120.380000 ;
      RECT 0.000000 116.720000 392.160000 119.480000 ;
      RECT 1.100000 115.820000 391.060000 116.720000 ;
      RECT 0.000000 111.230000 392.160000 115.820000 ;
      RECT 0.000000 110.330000 391.060000 111.230000 ;
      RECT 0.000000 106.960000 392.160000 110.330000 ;
      RECT 1.100000 106.060000 392.160000 106.960000 ;
      RECT 0.000000 97.810000 392.160000 106.060000 ;
      RECT 1.100000 96.910000 392.160000 97.810000 ;
      RECT 0.000000 94.760000 392.160000 96.910000 ;
      RECT 1.100000 93.860000 392.160000 94.760000 ;
      RECT 0.000000 89.880000 392.160000 93.860000 ;
      RECT 0.000000 88.980000 391.060000 89.880000 ;
      RECT 0.000000 84.390000 392.160000 88.980000 ;
      RECT 1.100000 83.490000 391.060000 84.390000 ;
      RECT 0.000000 77.070000 392.160000 83.490000 ;
      RECT 1.100000 76.170000 392.160000 77.070000 ;
      RECT 0.000000 0.000000 392.160000 76.170000 ;
    LAYER met4 ;
      RECT 203.640000 385.920000 392.160000 387.020000 ;
      RECT 187.035000 385.920000 202.740000 387.020000 ;
      RECT 178.425000 385.920000 186.135000 387.020000 ;
      RECT 163.665000 385.920000 177.525000 387.020000 ;
      RECT 0.000000 385.920000 162.765000 387.020000 ;
      RECT 0.000000 1.100000 392.160000 385.920000 ;
      RECT 221.475000 0.000000 392.160000 1.100000 ;
      RECT 207.330000 0.000000 220.575000 1.100000 ;
      RECT 201.180000 0.000000 206.430000 1.100000 ;
      RECT 187.035000 0.000000 200.280000 1.100000 ;
      RECT 136.605000 0.000000 186.135000 1.100000 ;
      RECT 0.000000 0.000000 135.705000 1.100000 ;
    LAYER met5 ;
      RECT 0.000000 313.870000 392.160000 387.020000 ;
      RECT 0.000000 309.070000 388.060000 313.870000 ;
      RECT 0.000000 266.290000 392.160000 309.070000 ;
      RECT 4.100000 261.490000 392.160000 266.290000 ;
      RECT 0.000000 240.670000 392.160000 261.490000 ;
      RECT 4.100000 235.870000 392.160000 240.670000 ;
      RECT 0.000000 233.350000 392.160000 235.870000 ;
      RECT 4.100000 228.550000 388.060000 233.350000 ;
      RECT 0.000000 222.370000 392.160000 228.550000 ;
      RECT 4.100000 217.570000 388.060000 222.370000 ;
      RECT 0.000000 211.390000 392.160000 217.570000 ;
      RECT 0.000000 207.730000 388.060000 211.390000 ;
      RECT 4.100000 206.590000 388.060000 207.730000 ;
      RECT 4.100000 202.930000 392.160000 206.590000 ;
      RECT 0.000000 200.410000 392.160000 202.930000 ;
      RECT 4.100000 195.610000 392.160000 200.410000 ;
      RECT 0.000000 167.470000 392.160000 195.610000 ;
      RECT 0.000000 162.670000 388.060000 167.470000 ;
      RECT 0.000000 160.150000 392.160000 162.670000 ;
      RECT 4.100000 155.350000 388.060000 160.150000 ;
      RECT 0.000000 152.830000 392.160000 155.350000 ;
      RECT 4.100000 148.030000 392.160000 152.830000 ;
      RECT 0.000000 127.210000 392.160000 148.030000 ;
      RECT 4.100000 122.410000 388.060000 127.210000 ;
      RECT 0.000000 112.570000 392.160000 122.410000 ;
      RECT 0.000000 107.770000 388.060000 112.570000 ;
      RECT 0.000000 0.000000 392.160000 107.770000 ;
  END
END mdu_macro

END LIBRARY
